VERSION 5.7 ;
BUSBITCHARS "[]" ;
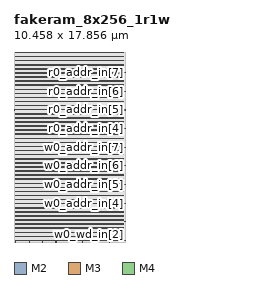
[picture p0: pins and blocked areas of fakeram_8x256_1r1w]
MACRO fakeram_8x256_1r1w
  FOREIGN fakeram_8x256_1r1w 0 0 ;
  SYMMETRY X Y R90 ;
  SIZE 10.458 BY 17.856 ;
  CLASS BLOCK ;
  PIN w0_wd_in[0]
    DIRECTION INPUT ;
    USE SIGNAL ;
    SHAPE ABUTMENT ;
    PORT
      LAYER M2 ;
      RECT 0.000 0.138 0.036 0.150 ;
    END
  END w0_wd_in[0]
  PIN w0_wd_in[1]
    DIRECTION INPUT ;
    USE SIGNAL ;
    SHAPE ABUTMENT ;
    PORT
      LAYER M2 ;
      RECT 0.000 1.890 0.036 1.902 ;
    END
  END w0_wd_in[1]
  PIN w0_wd_in[2]
    DIRECTION INPUT ;
    USE SIGNAL ;
    SHAPE ABUTMENT ;
    PORT
      LAYER M2 ;
      RECT 10.422 0.138 10.458 0.150 ;
    END
  END w0_wd_in[2]
  PIN w0_wd_in[3]
    DIRECTION INPUT ;
    USE SIGNAL ;
    SHAPE ABUTMENT ;
    PORT
      LAYER M2 ;
      RECT 10.422 1.890 10.458 1.902 ;
    END
  END w0_wd_in[3]
  PIN w0_wd_in[4]
    DIRECTION INPUT ;
    USE SIGNAL ;
    SHAPE ABUTMENT ;
    PORT
      LAYER M3 ;
      RECT 0.161 0.000 0.175 0.042 ;
    END
  END w0_wd_in[4]
  PIN w0_wd_in[5]
    DIRECTION INPUT ;
    USE SIGNAL ;
    SHAPE ABUTMENT ;
    PORT
      LAYER M3 ;
      RECT 1.421 0.000 1.435 0.042 ;
    END
  END w0_wd_in[5]
  PIN w0_wd_in[6]
    DIRECTION INPUT ;
    USE SIGNAL ;
    SHAPE ABUTMENT ;
    PORT
      LAYER M3 ;
      RECT 2.681 0.000 2.695 0.042 ;
    END
  END w0_wd_in[6]
  PIN w0_wd_in[7]
    DIRECTION INPUT ;
    USE SIGNAL ;
    SHAPE ABUTMENT ;
    PORT
      LAYER M3 ;
      RECT 3.941 0.000 3.955 0.042 ;
    END
  END w0_wd_in[7]
  PIN r0_rd_out[0]
    DIRECTION OUTPUT ;
    USE SIGNAL ;
    SHAPE ABUTMENT ;
    PORT
      LAYER M3 ;
      RECT 5.201 0.000 5.215 0.042 ;
    END
  END r0_rd_out[0]
  PIN r0_rd_out[1]
    DIRECTION OUTPUT ;
    USE SIGNAL ;
    SHAPE ABUTMENT ;
    PORT
      LAYER M3 ;
      RECT 6.461 0.000 6.475 0.042 ;
    END
  END r0_rd_out[1]
  PIN r0_rd_out[2]
    DIRECTION OUTPUT ;
    USE SIGNAL ;
    SHAPE ABUTMENT ;
    PORT
      LAYER M3 ;
      RECT 7.721 0.000 7.735 0.042 ;
    END
  END r0_rd_out[2]
  PIN r0_rd_out[3]
    DIRECTION OUTPUT ;
    USE SIGNAL ;
    SHAPE ABUTMENT ;
    PORT
      LAYER M3 ;
      RECT 8.981 0.000 8.995 0.042 ;
    END
  END r0_rd_out[3]
  PIN r0_rd_out[4]
    DIRECTION OUTPUT ;
    USE SIGNAL ;
    SHAPE ABUTMENT ;
    PORT
      LAYER M3 ;
      RECT 0.161 17.814 0.175 17.856 ;
    END
  END r0_rd_out[4]
  PIN r0_rd_out[5]
    DIRECTION OUTPUT ;
    USE SIGNAL ;
    SHAPE ABUTMENT ;
    PORT
      LAYER M3 ;
      RECT 1.281 17.814 1.295 17.856 ;
    END
  END r0_rd_out[5]
  PIN r0_rd_out[6]
    DIRECTION OUTPUT ;
    USE SIGNAL ;
    SHAPE ABUTMENT ;
    PORT
      LAYER M3 ;
      RECT 2.401 17.814 2.415 17.856 ;
    END
  END r0_rd_out[6]
  PIN r0_rd_out[7]
    DIRECTION OUTPUT ;
    USE SIGNAL ;
    SHAPE ABUTMENT ;
    PORT
      LAYER M3 ;
      RECT 3.521 17.814 3.535 17.856 ;
    END
  END r0_rd_out[7]
  PIN w0_addr_in[0]
    DIRECTION INPUT ;
    USE SIGNAL ;
    SHAPE ABUTMENT ;
    PORT
      LAYER M2 ;
      RECT 0.000 3.642 0.036 3.654 ;
    END
  END w0_addr_in[0]
  PIN w0_addr_in[1]
    DIRECTION INPUT ;
    USE SIGNAL ;
    SHAPE ABUTMENT ;
    PORT
      LAYER M2 ;
      RECT 0.000 5.394 0.036 5.406 ;
    END
  END w0_addr_in[1]
  PIN w0_addr_in[2]
    DIRECTION INPUT ;
    USE SIGNAL ;
    SHAPE ABUTMENT ;
    PORT
      LAYER M2 ;
      RECT 0.000 7.146 0.036 7.158 ;
    END
  END w0_addr_in[2]
  PIN w0_addr_in[3]
    DIRECTION INPUT ;
    USE SIGNAL ;
    SHAPE ABUTMENT ;
    PORT
      LAYER M2 ;
      RECT 0.000 8.898 0.036 8.910 ;
    END
  END w0_addr_in[3]
  PIN w0_addr_in[4]
    DIRECTION INPUT ;
    USE SIGNAL ;
    SHAPE ABUTMENT ;
    PORT
      LAYER M2 ;
      RECT 10.422 3.642 10.458 3.654 ;
    END
  END w0_addr_in[4]
  PIN w0_addr_in[5]
    DIRECTION INPUT ;
    USE SIGNAL ;
    SHAPE ABUTMENT ;
    PORT
      LAYER M2 ;
      RECT 10.422 5.394 10.458 5.406 ;
    END
  END w0_addr_in[5]
  PIN w0_addr_in[6]
    DIRECTION INPUT ;
    USE SIGNAL ;
    SHAPE ABUTMENT ;
    PORT
      LAYER M2 ;
      RECT 10.422 7.146 10.458 7.158 ;
    END
  END w0_addr_in[6]
  PIN w0_addr_in[7]
    DIRECTION INPUT ;
    USE SIGNAL ;
    SHAPE ABUTMENT ;
    PORT
      LAYER M2 ;
      RECT 10.422 8.898 10.458 8.910 ;
    END
  END w0_addr_in[7]
  PIN r0_addr_in[0]
    DIRECTION INPUT ;
    USE SIGNAL ;
    SHAPE ABUTMENT ;
    PORT
      LAYER M2 ;
      RECT 0.000 10.650 0.036 10.662 ;
    END
  END r0_addr_in[0]
  PIN r0_addr_in[1]
    DIRECTION INPUT ;
    USE SIGNAL ;
    SHAPE ABUTMENT ;
    PORT
      LAYER M2 ;
      RECT 0.000 12.402 0.036 12.414 ;
    END
  END r0_addr_in[1]
  PIN r0_addr_in[2]
    DIRECTION INPUT ;
    USE SIGNAL ;
    SHAPE ABUTMENT ;
    PORT
      LAYER M2 ;
      RECT 0.000 14.154 0.036 14.166 ;
    END
  END r0_addr_in[2]
  PIN r0_addr_in[3]
    DIRECTION INPUT ;
    USE SIGNAL ;
    SHAPE ABUTMENT ;
    PORT
      LAYER M2 ;
      RECT 0.000 15.906 0.036 15.918 ;
    END
  END r0_addr_in[3]
  PIN r0_addr_in[4]
    DIRECTION INPUT ;
    USE SIGNAL ;
    SHAPE ABUTMENT ;
    PORT
      LAYER M2 ;
      RECT 10.422 10.650 10.458 10.662 ;
    END
  END r0_addr_in[4]
  PIN r0_addr_in[5]
    DIRECTION INPUT ;
    USE SIGNAL ;
    SHAPE ABUTMENT ;
    PORT
      LAYER M2 ;
      RECT 10.422 12.402 10.458 12.414 ;
    END
  END r0_addr_in[5]
  PIN r0_addr_in[6]
    DIRECTION INPUT ;
    USE SIGNAL ;
    SHAPE ABUTMENT ;
    PORT
      LAYER M2 ;
      RECT 10.422 14.154 10.458 14.166 ;
    END
  END r0_addr_in[6]
  PIN r0_addr_in[7]
    DIRECTION INPUT ;
    USE SIGNAL ;
    SHAPE ABUTMENT ;
    PORT
      LAYER M2 ;
      RECT 10.422 15.906 10.458 15.918 ;
    END
  END r0_addr_in[7]
  PIN w0_we_in
    DIRECTION INPUT ;
    USE SIGNAL ;
    SHAPE ABUTMENT ;
    PORT
      LAYER M3 ;
      RECT 4.641 17.814 4.655 17.856 ;
    END
  END w0_we_in
  PIN w0_ce_in
    DIRECTION INPUT ;
    USE SIGNAL ;
    SHAPE ABUTMENT ;
    PORT
      LAYER M3 ;
      RECT 5.761 17.814 5.775 17.856 ;
    END
  END w0_ce_in
  PIN w0_clk
    DIRECTION INPUT ;
    USE SIGNAL ;
    SHAPE ABUTMENT ;
    PORT
      LAYER M3 ;
      RECT 6.881 17.814 6.895 17.856 ;
    END
  END w0_clk
  PIN r0_ce_in
    DIRECTION INPUT ;
    USE SIGNAL ;
    SHAPE ABUTMENT ;
    PORT
      LAYER M3 ;
      RECT 8.001 17.814 8.015 17.856 ;
    END
  END r0_ce_in
  PIN r0_clk
    DIRECTION INPUT ;
    USE SIGNAL ;
    SHAPE ABUTMENT ;
    PORT
      LAYER M3 ;
      RECT 9.121 17.814 9.135 17.856 ;
    END
  END r0_clk
  PIN VSS
    DIRECTION INOUT ;
    USE GROUND ;
    PORT
      LAYER M4 ;
      RECT 0.168 0.120 10.290 0.168 ;
      RECT 0.168 0.504 10.290 0.552 ;
      RECT 0.168 0.888 10.290 0.936 ;
      RECT 0.168 1.272 10.290 1.320 ;
      RECT 0.168 1.656 10.290 1.704 ;
      RECT 0.168 2.040 10.290 2.088 ;
      RECT 0.168 2.424 10.290 2.472 ;
      RECT 0.168 2.808 10.290 2.856 ;
      RECT 0.168 3.192 10.290 3.240 ;
      RECT 0.168 3.576 10.290 3.624 ;
      RECT 0.168 3.960 10.290 4.008 ;
      RECT 0.168 4.344 10.290 4.392 ;
      RECT 0.168 4.728 10.290 4.776 ;
      RECT 0.168 5.112 10.290 5.160 ;
      RECT 0.168 5.496 10.290 5.544 ;
      RECT 0.168 5.880 10.290 5.928 ;
      RECT 0.168 6.264 10.290 6.312 ;
      RECT 0.168 6.648 10.290 6.696 ;
      RECT 0.168 7.032 10.290 7.080 ;
      RECT 0.168 7.416 10.290 7.464 ;
      RECT 0.168 7.800 10.290 7.848 ;
      RECT 0.168 8.184 10.290 8.232 ;
      RECT 0.168 8.568 10.290 8.616 ;
      RECT 0.168 8.952 10.290 9.000 ;
      RECT 0.168 9.336 10.290 9.384 ;
      RECT 0.168 9.720 10.290 9.768 ;
      RECT 0.168 10.104 10.290 10.152 ;
      RECT 0.168 10.488 10.290 10.536 ;
      RECT 0.168 10.872 10.290 10.920 ;
      RECT 0.168 11.256 10.290 11.304 ;
      RECT 0.168 11.640 10.290 11.688 ;
      RECT 0.168 12.024 10.290 12.072 ;
      RECT 0.168 12.408 10.290 12.456 ;
      RECT 0.168 12.792 10.290 12.840 ;
      RECT 0.168 13.176 10.290 13.224 ;
      RECT 0.168 13.560 10.290 13.608 ;
      RECT 0.168 13.944 10.290 13.992 ;
      RECT 0.168 14.328 10.290 14.376 ;
      RECT 0.168 14.712 10.290 14.760 ;
      RECT 0.168 15.096 10.290 15.144 ;
      RECT 0.168 15.480 10.290 15.528 ;
      RECT 0.168 15.864 10.290 15.912 ;
      RECT 0.168 16.248 10.290 16.296 ;
      RECT 0.168 16.632 10.290 16.680 ;
      RECT 0.168 17.016 10.290 17.064 ;
      RECT 0.168 17.400 10.290 17.448 ;
      RECT 0.168 17.784 10.290 17.832 ;
    END
  END VSS
  PIN VDD
    DIRECTION INOUT ;
    USE POWER ;
    PORT
      LAYER M4 ;
      RECT 0.168 0.120 10.290 0.168 ;
      RECT 0.168 0.504 10.290 0.552 ;
      RECT 0.168 0.888 10.290 0.936 ;
      RECT 0.168 1.272 10.290 1.320 ;
      RECT 0.168 1.656 10.290 1.704 ;
      RECT 0.168 2.040 10.290 2.088 ;
      RECT 0.168 2.424 10.290 2.472 ;
      RECT 0.168 2.808 10.290 2.856 ;
      RECT 0.168 3.192 10.290 3.240 ;
      RECT 0.168 3.576 10.290 3.624 ;
      RECT 0.168 3.960 10.290 4.008 ;
      RECT 0.168 4.344 10.290 4.392 ;
      RECT 0.168 4.728 10.290 4.776 ;
      RECT 0.168 5.112 10.290 5.160 ;
      RECT 0.168 5.496 10.290 5.544 ;
      RECT 0.168 5.880 10.290 5.928 ;
      RECT 0.168 6.264 10.290 6.312 ;
      RECT 0.168 6.648 10.290 6.696 ;
      RECT 0.168 7.032 10.290 7.080 ;
      RECT 0.168 7.416 10.290 7.464 ;
      RECT 0.168 7.800 10.290 7.848 ;
      RECT 0.168 8.184 10.290 8.232 ;
      RECT 0.168 8.568 10.290 8.616 ;
      RECT 0.168 8.952 10.290 9.000 ;
      RECT 0.168 9.336 10.290 9.384 ;
      RECT 0.168 9.720 10.290 9.768 ;
      RECT 0.168 10.104 10.290 10.152 ;
      RECT 0.168 10.488 10.290 10.536 ;
      RECT 0.168 10.872 10.290 10.920 ;
      RECT 0.168 11.256 10.290 11.304 ;
      RECT 0.168 11.640 10.290 11.688 ;
      RECT 0.168 12.024 10.290 12.072 ;
      RECT 0.168 12.408 10.290 12.456 ;
      RECT 0.168 12.792 10.290 12.840 ;
      RECT 0.168 13.176 10.290 13.224 ;
      RECT 0.168 13.560 10.290 13.608 ;
      RECT 0.168 13.944 10.290 13.992 ;
      RECT 0.168 14.328 10.290 14.376 ;
      RECT 0.168 14.712 10.290 14.760 ;
      RECT 0.168 15.096 10.290 15.144 ;
      RECT 0.168 15.480 10.290 15.528 ;
      RECT 0.168 15.864 10.290 15.912 ;
      RECT 0.168 16.248 10.290 16.296 ;
      RECT 0.168 16.632 10.290 16.680 ;
      RECT 0.168 17.016 10.290 17.064 ;
      RECT 0.168 17.400 10.290 17.448 ;
      RECT 0.168 17.784 10.290 17.832 ;
    END
  END VDD
  OBS
    LAYER M1 ;
    RECT 0 0 10.458 17.856 ;
    LAYER M2 ;
    RECT 0 0 10.458 17.856 ;
    LAYER M3 ;
    RECT 0 0 10.458 17.856 ;
    LAYER M4 ;
    RECT 0 0 10.458 17.856 ;
  END
END fakeram_8x256_1r1w

END LIBRARY
